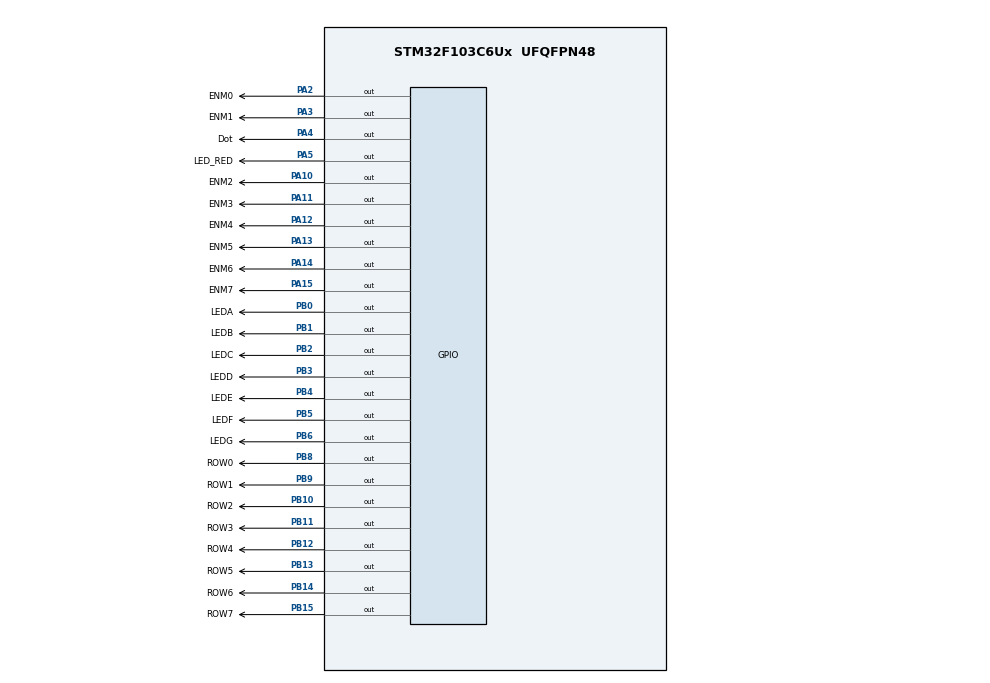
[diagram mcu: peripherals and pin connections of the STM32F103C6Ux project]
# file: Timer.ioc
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Mcu.Family=STM32F1
Mcu.Name=STM32F103C6Ux
Mcu.Package=UFQFPN48
NVIC.PriorityGroup=NVIC_PRIORITYGROUP_4
NVIC.TIM2_IRQn=true\:0\:0\:false\:false\:true\:true\:true
PA10.GPIO_Label=ENM2
PA10.Signal=GPIO_Output
PA11.GPIO_Label=ENM3
PA11.Signal=GPIO_Output
PA12.GPIO_Label=ENM4
PA12.Signal=GPIO_Output
PA13.GPIO_Label=ENM5
PA13.Signal=GPIO_Output
PA14.GPIO_Label=ENM6
PA14.Signal=GPIO_Output
PA15.GPIO_Label=ENM7
PA15.Signal=GPIO_Output
PA2.GPIO_Label=ENM0
PA2.Signal=GPIO_Output
PA3.GPIO_Label=ENM1
PA3.Signal=GPIO_Output
PA4.GPIO_Label=Dot
PA4.Signal=GPIO_Output
PA5.GPIO_Label=LED_RED
PA5.Signal=GPIO_Output
PB0.GPIO_Label=LEDA
PB0.Signal=GPIO_Output
PB1.GPIO_Label=LEDB
PB1.Signal=GPIO_Output
PB10.GPIO_Label=ROW2
PB10.Signal=GPIO_Output
PB11.GPIO_Label=ROW3
PB11.Signal=GPIO_Output
PB12.GPIO_Label=ROW4
PB12.Signal=GPIO_Output
PB13.GPIO_Label=ROW5
PB13.Signal=GPIO_Output
PB14.GPIO_Label=ROW6
PB14.Signal=GPIO_Output
PB15.GPIO_Label=ROW7
PB15.Signal=GPIO_Output
PB2.GPIO_Label=LEDC
PB2.Signal=GPIO_Output
PB3.GPIO_Label=LEDD
PB3.Signal=GPIO_Output
PB4.GPIO_Label=LEDE
PB4.Signal=GPIO_Output
PB5.GPIO_Label=LEDF
PB5.Signal=GPIO_Output
PB6.GPIO_Label=LEDG
PB6.Signal=GPIO_Output
PB8.GPIO_Label=ROW0
PB8.Signal=GPIO_Output
PB9.GPIO_Label=ROW1
PB9.Signal=GPIO_Output
ProjectManager.HeapSize=0x200
ProjectManager.StackSize=0x400
ProjectManager.TargetToolchain=STM32CubeIDE
RCC.APB1Freq_Value=8000000
RCC.APB2Freq_Value=8000000
TIM2.Period=9
TIM2.Prescaler=7999
VP_SYS_VS_ND.Mode=No_Debug
VP_TIM2_VS_ClockSourceINT.Mode=Internal
board=custom

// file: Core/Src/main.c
/* USER CODE BEGIN Header */
/**
  ******************************************************************************
  * @file           : main.c
  * @brief          : Main program body
  ******************************************************************************
  * @attention
  *
  * <h2><center>&copy; Copyright (c) 2024 STMicroelectronics.
  * All rights reserved.</center></h2>
  *
  * This software component is licensed by ST under BSD 3-Clause license,
  * the "License"; You may not use this file except in compliance with the
  * License. You may obtain a copy of the License at:
  *                        opensource.org/licenses/BSD-3-Clause
  *
  ******************************************************************************
  */
/* USER CODE END Header */
#include "main.h"

/* USER CODE BEGIN Includes */
#include "software_timer.h"

/* USER CODE END Includes */

TIM_HandleTypeDef htim2;

/* USER CODE BEGIN PV */
int hour = 15, minute = 8, second = 50;
/* USER CODE END PV */

void SystemClock_Config(void);
static void MX_GPIO_Init(void);
static void MX_TIM2_Init(void);

int main(void)
{

  /* MCU Configuration--------------------------------------------------------*/

  /* Reset of all peripherals, Initializes the Flash interface and the Systick. */
  HAL_Init();

  /* Configure the system clock */
  SystemClock_Config();

  /* Initialize all configured peripherals */
  MX_GPIO_Init();
  MX_TIM2_Init();
  /* USER CODE BEGIN 2 */
  HAL_TIM_Base_Start_IT(&htim2);
  /* USER CODE END 2 */

  /* Infinite loop */
  /* USER CODE BEGIN WHILE */
  setTimer1(100);
  setTimer2(100);
  updateClockBuffer();
  while (1)
  {
	  if(timer1_flag == 1){
		  setTimer1(100);
		  HAL_GPIO_TogglePin(Dot_GPIO_Port, Dot_Pin);
		  second++;
		  if (second >= 60){
			  second = 0;
			  minute++;
		  }
		  if(minute >= 60){
			  minute = 0;
			  hour++;
		  }
		  if(hour >=24){
			  hour = 0;
		  }
	  }
	  if(timer2_flag == 1){
		  updateClockBuffer();
		  setTimer2(25);
	  }
    /* USER CODE END WHILE */

  }
}

void SystemClock_Config(void)
{
  RCC_OscInitTypeDef RCC_OscInitStruct = {0};
  RCC_ClkInitTypeDef RCC_ClkInitStruct = {0};

  /** Initializes the RCC Oscillators according to the specified parameters
  * in the RCC_OscInitTypeDef structure.
  */
  RCC_OscInitStruct.OscillatorType = RCC_OSCILLATORTYPE_HSI;
  RCC_OscInitStruct.HSIState = RCC_HSI_ON;
  RCC_OscInitStruct.HSICalibrationValue = RCC_HSICALIBRATION_DEFAULT;
  RCC_OscInitStruct.PLL.PLLState = RCC_PLL_NONE;
  if (HAL_RCC_OscConfig(&RCC_OscInitStruct) != HAL_OK)
  {
    Error_Handler();
  }
  /** Initializes the CPU, AHB and APB buses clocks
  */
  RCC_ClkInitStruct.ClockType = RCC_CLOCKTYPE_HCLK|RCC_CLOCKTYPE_SYSCLK
                              |RCC_CLOCKTYPE_PCLK1|RCC_CLOCKTYPE_PCLK2;
  RCC_ClkInitStruct.SYSCLKSource = RCC_SYSCLKSOURCE_HSI;
  RCC_ClkInitStruct.AHBCLKDivider = RCC_SYSCLK_DIV1;
  RCC_ClkInitStruct.APB1CLKDivider = RCC_HCLK_DIV1;
  RCC_ClkInitStruct.APB2CLKDivider = RCC_HCLK_DIV1;

  if (HAL_RCC_ClockConfig(&RCC_ClkInitStruct, FLASH_LATENCY_0) != HAL_OK)
  {
    Error_Handler();
  }
}

static void MX_TIM2_Init(void)
{

  TIM_ClockConfigTypeDef sClockSourceConfig = {0};
  TIM_MasterConfigTypeDef sMasterConfig = {0};

  htim2.Instance = TIM2;
  htim2.Init.Prescaler = 7999;
  htim2.Init.CounterMode = TIM_COUNTERMODE_UP;
  htim2.Init.Period = 9;
  htim2.Init.ClockDivision = TIM_CLOCKDIVISION_DIV1;
  htim2.Init.AutoReloadPreload = TIM_AUTORELOAD_PRELOAD_DISABLE;
  if (HAL_TIM_Base_Init(&htim2) != HAL_OK)
  {
    Error_Handler();
  }
  sClockSourceConfig.ClockSource = TIM_CLOCKSOURCE_INTERNAL;
  if (HAL_TIM_ConfigClockSource(&htim2, &sClockSourceConfig) != HAL_OK)
  {
    Error_Handler();
  }
  sMasterConfig.MasterOutputTrigger = TIM_TRGO_RESET;
  sMasterConfig.MasterSlaveMode = TIM_MASTERSLAVEMODE_DISABLE;
  if (HAL_TIMEx_MasterConfigSynchronization(&htim2, &sMasterConfig) != HAL_OK)
  {
    Error_Handler();
  }

}

static void MX_GPIO_Init(void)
{
  GPIO_InitTypeDef GPIO_InitStruct = {0};

  /* GPIO Ports Clock Enable */
  __HAL_RCC_GPIOA_CLK_ENABLE();
  __HAL_RCC_GPIOB_CLK_ENABLE();

  /*Configure GPIO pin Output Level */
  HAL_GPIO_WritePin(GPIOA, Dot_Pin|LED_RED_Pin|EN0_Pin|EN1_Pin
                          |EN2_Pin|EN3_Pin, GPIO_PIN_RESET);

  /*Configure GPIO pin Output Level */
  HAL_GPIO_WritePin(GPIOB, LEDA_Pin|LEDB_Pin|LEDC_Pin|LEDD_Pin
                          |LEDE_Pin|LEDF_Pin|LEDG_Pin, GPIO_PIN_RESET);

  /*Configure GPIO pins : Dot_Pin LED_RED_Pin EN0_Pin EN1_Pin
                           EN2_Pin EN3_Pin */
  GPIO_InitStruct.Pin = Dot_Pin|LED_RED_Pin|EN0_Pin|EN1_Pin
                          |EN2_Pin|EN3_Pin;
  GPIO_InitStruct.Mode = GPIO_MODE_OUTPUT_PP;
  GPIO_InitStruct.Pull = GPIO_NOPULL;
  GPIO_InitStruct.Speed = GPIO_SPEED_FREQ_LOW;
  HAL_GPIO_Init(GPIOA, &GPIO_InitStruct);

  /*Configure GPIO pins : LEDA_Pin LEDB_Pin LEDC_Pin LEDD_Pin
                           LEDE_Pin LEDF_Pin LEDG_Pin */
  GPIO_InitStruct.Pin = LEDA_Pin|LEDB_Pin|LEDC_Pin|LEDD_Pin
                          |LEDE_Pin|LEDF_Pin|LEDG_Pin;
  GPIO_InitStruct.Mode = GPIO_MODE_OUTPUT_PP;
  GPIO_InitStruct.Pull = GPIO_NOPULL;
  GPIO_InitStruct.Speed = GPIO_SPEED_FREQ_LOW;
  HAL_GPIO_Init(GPIOB, &GPIO_InitStruct);

}

/* USER CODE BEGIN 4 */
void HAL_TIM_PeriodElapsedCallback(TIM_HandleTypeDef *htim){
	timerRun();
}
/* USER CODE END 4 */

void Error_Handler(void)
{
  __disable_irq();
  while (1)
  {
  }
}

/************************ (C) COPYRIGHT STMicroelectronics *****END OF FILE****/
